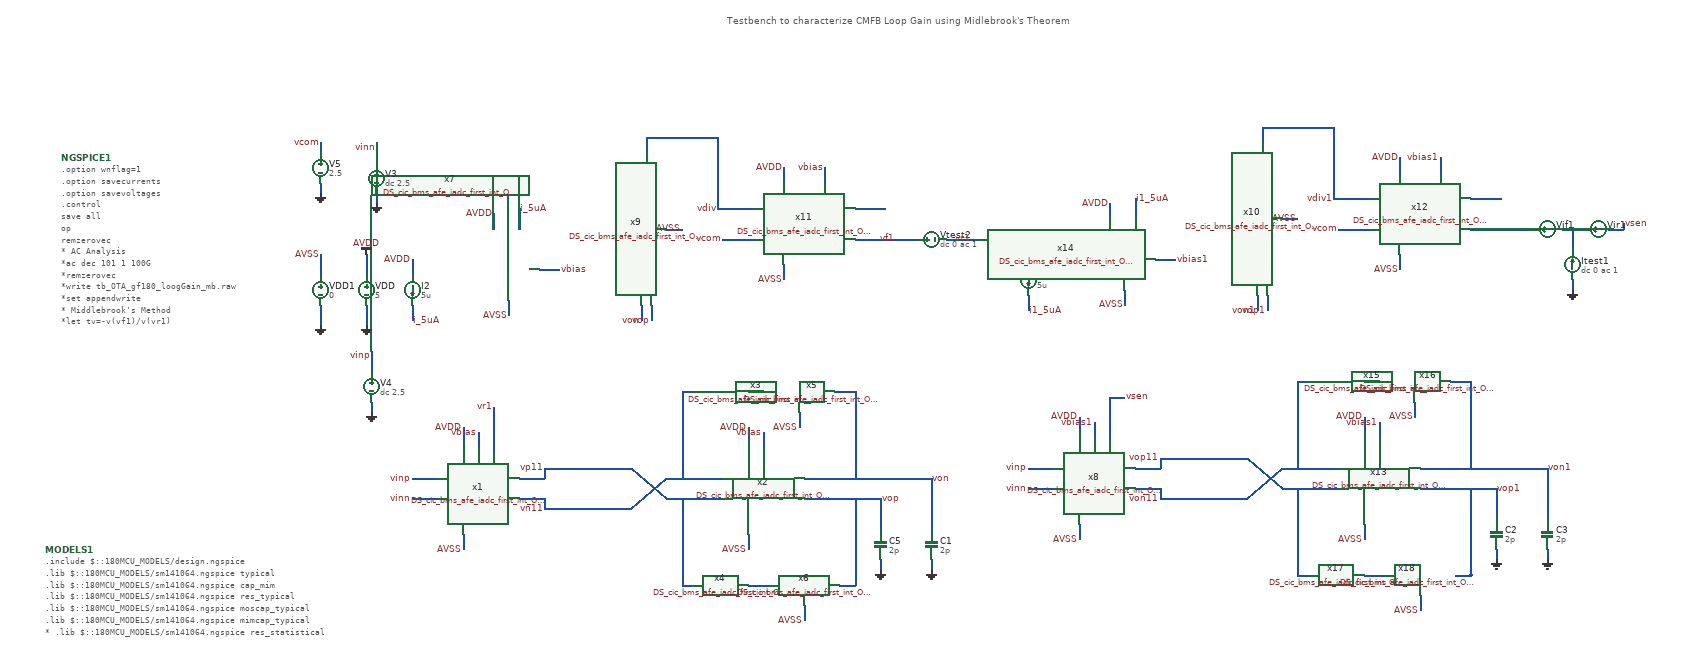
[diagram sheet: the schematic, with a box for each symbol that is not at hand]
v {xschem version=3.4.8RC file_version=1.3}
G {}
K {}
V {}
S {}
F {}
E {}
T {Testbench to characterize CMFB Loop Gain using Midlebrook's Theorem} 800 -610 0 0 0.4 0.4 {}
N 390 300 440 300 {
lab=vp11}
N 390 340 440 340 {
lab=vn11}
N 680 300 790 300 {
lab=vn11}
N 680 340 790 340 {
lab=vp11}
N 710 510 730 510 {
lab=vp11}
N 710 340 710 510 {
lab=vp11}
N 840 510 880 510 {
lab=#net1}
N 950 340 1100 340 {
lab=vop}
N 1020 510 1050 510 {
lab=vop}
N 1050 340 1050 510 {
lab=vop}
N 710 130 730 130 {
lab=vn11}
N 710 130 710 300 {
lab=vn11}
N 840 130 870 130 {
lab=#net2}
N 950 300 1100 300 {
lab=von}
N 1050 130 1050 300 {
lab=von}
N 1010 130 1050 130 {
lab=von}
N 370 -50 370 -20 {
lab=AVSS}
N 280 410 280 440 {
lab=AVSS}
N 280 200 280 230 {
lab=AVDD}
N 310 210 310 240 {
lab=vbias}
N 340 220 340 250 {
lab=vr1}
N 840 200 840 230 {
lab=AVDD}
N 870 210 870 240 {
lab=vbias}
N 840 410 840 440 {
lab=AVSS}
N 910 -310 910 -280 {
lab=AVDD}
N 910 -120 910 -90 {
lab=AVSS}
N 990 -310 990 -280 {
lab=vbias}
N 1050 -170 1080 -170 {
lab=vf1}
N 630 -40 630 -10 {
lab=von}
N 650 -40 650 -10 {
lab=vop}
N 180 300 230 300 {
lab=vinp}
N 180 340 230 340 {
lab=vinn}
N 780 -370 780 -230 {
lab=vdiv}
N 780 -230 850 -230 {
lab=vdiv}
N 390 -230 390 -190 {
lab=i_5uA}
N 790 -170 850 -170 {
lab=vcom}
N 1100 300 1200 300 {
lab=von}
N 440 280 510 280 {
lab=vp11}
N 440 280 440 300 {
lab=vp11}
N 440 360 510 360 {
lab=vn11}
N 440 340 440 360 {
lab=vn11}
N 940 170 940 200 {
lab=AVSS}
N 950 550 950 580 {
lab=AVSS}
N 640 -370 640 -340 {
lab=vdiv}
N 640 -370 780 -370 {
lab=vdiv}
N 680 -190 710 -190 {
lab=AVSS}
N 430 -110 470 -110 {
lab=vbias}
N 340 -220 340 -190 {
lab=AVDD}
N 510 280 610 280 {
lab=vp11}
N 510 360 610 360 {
lab=vn11}
N 90 -140 90 -100 {lab=AVDD}
N 90 -40 90 0 {lab=GND}
N 0 -140 0 -100 {lab=AVSS}
N 0 -40 0 0 {lab=GND}
N 1100 460 1100 480 {
lab=GND}
N 1200 460 1200 480 {
lab=GND}
N 1200 300 1200 400 {lab=von}
N 1100 340 1100 400 {lab=vop}
N 110 -260 110 -240 {
lab=GND}
N 100 150 100 170 {
lab=GND}
N 110 -360 110 -320 {
lab=vinn}
N 100 50 100 90 {
lab=vinp}
N 180 -40 180 -10 {
lab=i_5uA}
N 180 -130 180 -100 {
lab=AVDD}
N 0 -280 0 -260 {
lab=GND}
N 0 -360 0 -340 {
lab=vcom}
N 1050 -230 1110 -230 {lab=#net3}
N 1090 -170 1170 -170 {lab=vf1}
N 1080 -170 1090 -170 {lab=vf1}
N 1230 -170 1290 -170 {lab=vr1}
N 340 160 340 220 {lab=vr1}
N 1600 280 1650 280 {
lab=vop11}
N 1600 320 1650 320 {
lab=von11}
N 1890 280 2000 280 {
lab=von11}
N 1890 320 2000 320 {
lab=vop11}
N 1920 490 1940 490 {
lab=vop11}
N 1920 320 1920 490 {
lab=vop11}
N 2050 490 2090 490 {
lab=#net4}
N 2160 320 2310 320 {
lab=vop1}
N 2230 490 2260 490 {
lab=vop1}
N 2260 320 2260 490 {
lab=vop1}
N 1920 110 1940 110 {
lab=von11}
N 1920 110 1920 280 {
lab=von11}
N 2050 110 2080 110 {
lab=#net5}
N 2160 280 2310 280 {
lab=von1}
N 2260 110 2260 280 {
lab=von1}
N 2220 110 2260 110 {
lab=von1}
N 1580 -70 1580 -40 {
lab=AVSS}
N 1490 390 1490 420 {
lab=AVSS}
N 1490 180 1490 210 {
lab=AVDD}
N 1520 190 1520 220 {
lab=vbias1}
N 1550 200 1550 230 {
lab=vsen}
N 2050 180 2050 210 {
lab=AVDD}
N 2080 190 2080 220 {
lab=vbias1}
N 2050 390 2050 420 {
lab=AVSS}
N 2120 -330 2120 -300 {
lab=AVDD}
N 2120 -140 2120 -110 {
lab=AVSS}
N 2200 -330 2200 -300 {
lab=vbias1}
N 2260 -190 2290 -190 {
lab=#net6}
N 1840 -60 1840 -30 {
lab=von1}
N 1860 -60 1860 -30 {
lab=vop1}
N 1390 280 1440 280 {
lab=vinp}
N 1390 320 1440 320 {
lab=vinn}
N 1990 -390 1990 -250 {
lab=vdiv1}
N 1990 -250 2060 -250 {
lab=vdiv1}
N 1600 -250 1600 -210 {
lab=i1_5uA}
N 2000 -190 2060 -190 {
lab=vcom}
N 2310 280 2410 280 {
lab=von1}
N 1650 260 1720 260 {
lab=vop11}
N 1650 260 1650 280 {
lab=vop11}
N 1650 340 1720 340 {
lab=von11}
N 1650 320 1650 340 {
lab=von11}
N 2150 150 2150 180 {
lab=AVSS}
N 2160 530 2160 560 {
lab=AVSS}
N 1850 -390 1850 -360 {
lab=vdiv1}
N 1850 -390 1990 -390 {
lab=vdiv1}
N 1890 -210 1920 -210 {
lab=AVSS}
N 1640 -130 1680 -130 {
lab=vbias1}
N 1550 -240 1550 -210 {
lab=AVDD}
N 1720 260 1820 260 {
lab=vop11}
N 1720 340 1820 340 {
lab=von11}
N 2310 440 2310 460 {
lab=GND}
N 2410 440 2410 460 {
lab=GND}
N 2410 280 2410 380 {lab=von1}
N 2310 320 2310 380 {lab=vop1}
N 1390 -60 1390 -30 {
lab=i1_5uA}
N 1390 -150 1390 -120 {
lab=AVDD}
N 2260 -250 2320 -250 {lab=#net7}
N 2290 -190 2300 -190 {lab=#net6}
N 1550 140 1550 200 {lab=vsen}
N 2300 -190 2340 -190 {lab=#net6}
N 1550 140 1580 140 {lab=vsen}
N 610 360 680 300 {lab=vn11}
N 610 280 680 340 {lab=vp11}
N 1820 340 1890 280 {lab=von11}
N 1820 260 1890 320 {lab=vop11}
N 2460 -190 2480 -190 {
lab=#net8}
N 2460 -190 2460 -150 {lab=#net8}
N 2440 -190 2460 -190 {
lab=#net8}
N 2340 -190 2380 -190 {lab=#net6}
N 2460 -90 2460 -70 {lab=GND}
N 2560 -200 2560 -190 {lab=vsen}
N 2530 -190 2560 -190 {lab=vsen}
N 2230 490 2260 490 {
lab=vop1}
C {lab_pin.sym} 470 -110 2 0 {name=p12 sig_type=std_logic lab=vbias}
C {lab_pin.sym} 310 210 1 0 {name=p13 sig_type=std_logic lab=vbias}
C {lab_pin.sym} 870 210 1 0 {name=p14 sig_type=std_logic lab=vbias}
C {lab_pin.sym} 990 -310 1 0 {name=p15 sig_type=std_logic lab=vbias}
C {lab_pin.sym} 1200 300 2 0 {name=p16 sig_type=std_logic lab=von}
C {lab_pin.sym} 1100 340 2 0 {name=p17 sig_type=std_logic lab=vop}
C {lab_pin.sym} 630 -10 3 0 {name=p18 sig_type=std_logic lab=von}
C {lab_pin.sym} 650 -10 3 0 {name=p19 sig_type=std_logic lab=vop}
C {lab_pin.sym} 180 300 0 0 {name=p22 sig_type=std_logic lab=vinp}
C {lab_pin.sym} 180 340 0 0 {name=p23 sig_type=std_logic lab=vinn}
C {lab_pin.sym} 790 -170 0 0 {name=p29 sig_type=std_logic lab=vcom}
C {title.sym} 30 730 0 0 {name=l1 author="VSP"}
C {lab_pin.sym} 390 -230 2 0 {name=p38 sig_type=std_logic lab=i_5uA}
C {lab_pin.sym} 280 200 1 0 {name=p1 sig_type=std_logic lab=AVDD}
C {lab_pin.sym} 840 200 1 0 {name=p5 sig_type=std_logic lab=AVDD}
C {lab_pin.sym} 340 -220 1 0 {name=p6 sig_type=std_logic lab=AVDD}
C {lab_pin.sym} 910 -310 1 0 {name=p7 sig_type=std_logic lab=AVDD}
C {lab_pin.sym} 370 -20 3 0 {name=p39 sig_type=std_logic lab=AVSS}
C {lab_pin.sym} 710 -190 3 0 {name=p8 sig_type=std_logic lab=AVSS}
C {lab_pin.sym} 910 -90 3 0 {name=p9 sig_type=std_logic lab=AVSS}
C {lab_pin.sym} 840 440 3 0 {name=p10 sig_type=std_logic lab=AVSS}
C {lab_pin.sym} 940 200 3 0 {name=p11 sig_type=std_logic lab=AVSS}
C {lab_pin.sym} 950 580 3 0 {name=p35 sig_type=std_logic lab=AVSS}
C {DS_cic_bms_afe_iadc_first_int_OTA_gm1.sym} 310 320 0 0 {name=x1}
C {DS_cic_bms_afe_iadc_first_int_OTA_gm2.sym} 860 330 0 0 {name=x2}
C {DS_cic_bms_afe_iadc_first_int_OTA_miller_cap.sym} 790 130 0 0 {name=x3}
C {lab_pin.sym} 280 440 3 0 {name=p2 sig_type=std_logic lab=AVSS}
C {DS_cic_bms_afe_iadc_first_int_OTA_nulling_resistor.sym} 950 130 0 1 {name=x5}
C {DS_cic_bms_afe_iadc_first_int_OTA_bias_ckt.sym} 360 -120 0 0 {name=x7}
C {DS_cic_bms_afe_iadc_first_int_OTA_CMFB_resistor_divider.sym} 730 -190 3 0 {name=x9}
C {devices/vsource.sym} 90 -70 0 0 {name=VDD value=5}
C {devices/gnd.sym} 90 0 0 0 {name=l3 lab=GND}
C {devices/vdd.sym} 90 -140 0 0 {name=l7 lab=AVDD}
C {devices/vsource.sym} 0 -70 0 0 {name=VDD1 value=0}
C {devices/gnd.sym} 0 0 0 0 {name=l2 lab=GND}
C {lab_pin.sym} 0 -140 0 0 {name=p3 sig_type=std_logic lab=AVSS}
C {devices/code_shown.sym} -540 440 0 0 {name=MODELS1 only_toplevel=true
format="tcleval( @value )"
value="
.include $::180MCU_MODELS/design.ngspice
.lib $::180MCU_MODELS/sm141064.ngspice typical
.lib $::180MCU_MODELS/sm141064.ngspice cap_mim
.lib $::180MCU_MODELS/sm141064.ngspice res_typical
.lib $::180MCU_MODELS/sm141064.ngspice moscap_typical
.lib $::180MCU_MODELS/sm141064.ngspice mimcap_typical
* .lib $::180MCU_MODELS/sm141064.ngspice res_statistical
"}
C {capa.sym} 1100 430 0 0 {name=C5
m=1
value=2p
footprint=1206
device="ceramic capacitor"}
C {gnd.sym} 1100 480 0 0 {name=l9 lab=GND}
C {capa.sym} 1200 430 0 0 {name=C1
m=1
value=2p
footprint=1206
device="ceramic capacitor"}
C {gnd.sym} 1200 480 0 0 {name=l4 lab=GND}
C {vsource.sym} 110 -290 0 0 {name=V3 value="dc 2.5 " savecurrent=false}
C {gnd.sym} 110 -240 0 0 {name=l5 lab=GND}
C {vsource.sym} 100 120 0 0 {name=V4 value="dc 2.5 "  savecurrent=false}
C {gnd.sym} 100 170 0 0 {name=l6 lab=GND}
C {lab_pin.sym} 110 -350 0 0 {name=p4 sig_type=std_logic lab=vinn}
C {lab_pin.sym} 100 60 0 0 {name=p24 sig_type=std_logic lab=vinp}
C {isource.sym} 180 -70 0 0 {name=I2 value=5u}
C {lab_pin.sym} 180 -130 1 0 {name=p25 sig_type=std_logic lab=AVDD
}
C {lab_pin.sym} 180 -10 2 0 {name=p26 sig_type=std_logic lab=i_5uA}
C {vsource.sym} 0 -310 0 0 {name=V5 value=2.5 savecurrent=false}
C {gnd.sym} 0 -260 0 0 {name=l8 lab=GND}
C {lab_pin.sym} 0 -360 0 0 {name=p27 sig_type=std_logic lab=vcom
}
C {noconn.sym} 1110 -230 2 0 {name=l10}
C {devices/code_shown.sym} -510 -330 0 0 {name=NGSPICE1 only_toplevel=true
value="
.option wnflag=1
.option savecurrents
.option savevoltages
.control 
save all

op
remzerovec

* AC Analysis
*ac dec 101 1 100G
*remzerovec
*write tb_OTA_gf180_loogGain_mb.raw
*set appendwrite

* Middlebrook's Method
*let tv=-v(vf1)/v(vr1)
*let ti=-i(vif1)/i(vir1)
*let tmb=(tv*ti - 1)/(tv + ti + 2)

*let gain_db = db(tmb)
*let phase_unwrapped = 180/pi*cphase(tmb)

*plot gain_dB ylabel 'Magnitude '
*plot phase_unwrapped ylabel 'Phase '


*meas ac A0_db find gain_db at=10
*meas ac UGB when gain_db=0 fall=1
*meas ac PHASE_UGB find phase_unwrapped at=$&UGB


*let PM = 180 + PHASE_UGB

*print A0_db UGB PHASE_UGB pm

write tb_diff_amp_CMFB_loopGain_mb.raw
.endc
"


}
C {devices/launcher.sym} 280 -540 0 0 {name=h2
descr="Simulate" 
tclcommand="xschem save; xschem netlist; xschem simulate"
}
C {devices/launcher.sym} 280 -420 0 0 {name=h1
descr="Load waves" 
tclcommand="xschem raw_read $netlist_dir/ota-differential_tb-loopgain.raw ac"
}
C {devices/launcher.sym} 280 -480 0 0 {name=h3
descr="Annotate OP" 
tclcommand="set show_hidden_texts 1; xschem annotate_op"
}
C {lab_pin.sym} 440 280 0 0 {name=p28 sig_type=std_logic lab=vp11}
C {lab_pin.sym} 440 360 0 0 {name=p30 sig_type=std_logic lab=vn11}
C {lab_pin.sym} 780 -230 0 0 {name=p31 sig_type=std_logic lab=vdiv}
C {devices/vsource.sym} 1200 -170 3 0 {name=Vtest2 value="dc 0 ac 1"}
C {devices/lab_wire.sym} 1130 -170 0 0 {name=p32 sig_type=std_logic lab=vf1}
C {devices/lab_wire.sym} 1280 -170 0 0 {name=p33 sig_type=std_logic lab=vr1}
C {devices/lab_wire.sym} 340 160 0 0 {name=p20 sig_type=std_logic lab=vr1}
C {lab_pin.sym} 1680 -130 2 0 {name=p21 sig_type=std_logic lab=vbias1}
C {lab_pin.sym} 1520 190 1 0 {name=p34 sig_type=std_logic lab=vbias1}
C {lab_pin.sym} 2080 190 1 0 {name=p36 sig_type=std_logic lab=vbias1}
C {lab_pin.sym} 2200 -330 1 0 {name=p37 sig_type=std_logic lab=vbias1}
C {lab_pin.sym} 2410 280 2 0 {name=p40 sig_type=std_logic lab=von1}
C {lab_pin.sym} 2310 320 2 0 {name=p41 sig_type=std_logic lab=vop1}
C {lab_pin.sym} 1840 -30 3 0 {name=p42 sig_type=std_logic lab=von1}
C {lab_pin.sym} 1860 -30 3 0 {name=p43 sig_type=std_logic lab=vop1}
C {lab_pin.sym} 1390 280 0 0 {name=p44 sig_type=std_logic lab=vinp}
C {lab_pin.sym} 1390 320 0 0 {name=p45 sig_type=std_logic lab=vinn}
C {lab_pin.sym} 2000 -190 0 0 {name=p46 sig_type=std_logic lab=vcom}
C {lab_pin.sym} 1600 -250 2 0 {name=p47 sig_type=std_logic lab=i1_5uA}
C {lab_pin.sym} 1490 180 1 0 {name=p48 sig_type=std_logic lab=AVDD}
C {lab_pin.sym} 2050 180 1 0 {name=p49 sig_type=std_logic lab=AVDD}
C {lab_pin.sym} 1550 -240 1 0 {name=p50 sig_type=std_logic lab=AVDD}
C {lab_pin.sym} 2120 -330 1 0 {name=p51 sig_type=std_logic lab=AVDD}
C {lab_pin.sym} 1580 -40 3 0 {name=p52 sig_type=std_logic lab=AVSS}
C {lab_pin.sym} 1920 -210 3 0 {name=p53 sig_type=std_logic lab=AVSS}
C {lab_pin.sym} 2120 -110 3 0 {name=p54 sig_type=std_logic lab=AVSS}
C {lab_pin.sym} 2050 420 3 0 {name=p55 sig_type=std_logic lab=AVSS}
C {lab_pin.sym} 2150 180 3 0 {name=p56 sig_type=std_logic lab=AVSS}
C {lab_pin.sym} 2160 560 3 0 {name=p57 sig_type=std_logic lab=AVSS}
C {lab_pin.sym} 1490 420 3 0 {name=p58 sig_type=std_logic lab=AVSS}
C {capa.sym} 2310 410 0 0 {name=C2
m=1
value=2p
footprint=1206
device="ceramic capacitor"}
C {gnd.sym} 2310 460 0 0 {name=l11 lab=GND}
C {capa.sym} 2410 410 0 0 {name=C3
m=1
value=2p
footprint=1206
device="ceramic capacitor"}
C {gnd.sym} 2410 460 0 0 {name=l12 lab=GND}
C {isource.sym} 1390 -90 0 0 {name=I1 value=5u}
C {lab_pin.sym} 1390 -150 1 0 {name=p59 sig_type=std_logic lab=AVDD
}
C {lab_pin.sym} 1390 -30 2 0 {name=p60 sig_type=std_logic lab=i1_5uA}
C {noconn.sym} 2320 -250 2 0 {name=l13}
C {lab_pin.sym} 1650 260 0 0 {name=p61 sig_type=std_logic lab=vop11}
C {lab_pin.sym} 1650 340 0 0 {name=p62 sig_type=std_logic lab=von11}
C {lab_pin.sym} 1990 -250 0 0 {name=p63 sig_type=std_logic lab=vdiv1}
C {lab_pin.sym} 1580 140 2 0 {name=p65 sig_type=std_logic lab=vsen}
C {devices/ammeter.sym} 2510 -190 1 0 {name=Vir1 savecurrent=true spice_ignore=0}
C {devices/ammeter.sym} 2410 -190 1 0 {name=Vif1 savecurrent=true spice_ignore=0}
C {devices/isource.sym} 2460 -120 2 0 {name=Itest1 value="dc 0 ac 1"}
C {gnd.sym} 2460 -70 0 0 {name=l14 lab=GND}
C {lab_pin.sym} 2560 -200 2 0 {name=p64 sig_type=std_logic lab=vsen}
C {DS_cic_bms_afe_iadc_first_int_OTA_miller_cap.sym} 790 510 0 0 {name=x4}
C {DS_cic_bms_afe_iadc_first_int_OTA_nulling_resistor.sym} 960 510 0 1 {name=x6}
C {DS_cic_bms_afe_iadc_first_int_OTA_bias_ckt.sym} 1570 -140 0 0 {name=x14}
C {DS_cic_bms_afe_iadc_first_int_OTA_CMFB_resistor_divider.sym} 1940 -210 3 0 {name=x10}
C {DS_cic_bms_afe_iadc_first_int_OTA_CMFB.sym} 950 -200 0 0 {name=x11}
C {DS_cic_bms_afe_iadc_first_int_OTA_CMFB.sym} 2160 -220 0 0 {name=x12}
C {DS_cic_bms_afe_iadc_first_int_OTA_gm1.sym} 1520 300 0 0 {name=x8}
C {DS_cic_bms_afe_iadc_first_int_OTA_gm2.sym} 2070 310 0 0 {name=x13}
C {DS_cic_bms_afe_iadc_first_int_OTA_miller_cap.sym} 2000 110 0 0 {name=x15}
C {DS_cic_bms_afe_iadc_first_int_OTA_nulling_resistor.sym} 2160 110 0 1 {name=x16}
C {DS_cic_bms_afe_iadc_first_int_OTA_miller_cap.sym} 2000 490 0 0 {name=x17}
C {DS_cic_bms_afe_iadc_first_int_OTA_nulling_resistor.sym} 2170 490 0 1 {name=x18}
